VERSION 5.8 ;
BUSBITCHARS "[]" ;
DIVIDERCHAR "/" ;
UNITS
  DATABASE MICRONS 1000 ;
END UNITS
MANUFACTURINGGRID 0.005 ;
PROPERTYDEFINITIONS
  LAYER LEF58_CUTCLASS STRING ;
  LAYER LEF58_MINIMUMCUT STRING ;
END PROPERTYDEFINITIONS
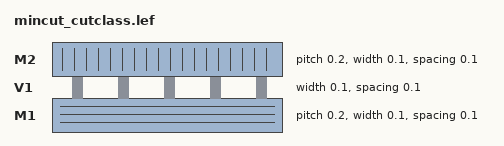
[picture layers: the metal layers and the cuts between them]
LAYER M1
  TYPE ROUTING ;
  DIRECTION HORIZONTAL ;
  PITCH 0.2 ;
  WIDTH 0.1 ;
  SPACING 0.1 ;
  PROPERTY LEF58_MINIMUMCUT "MINIMUMCUT 2 WIDTH 0.5 ;" ;
END M1
LAYER V1
  TYPE CUT ;
  SPACING 0.1 ;
  WIDTH 0.1 ;
  PROPERTY LEF58_CUTCLASS "CUTCLASS VA WIDTH 0.1 ; CUTCLASS VB WIDTH 0.1 LENGTH 0.2 ;" ;
END V1
LAYER M2
  TYPE ROUTING ;
  DIRECTION VERTICAL ;
  PITCH 0.2 ;
  WIDTH 0.1 ;
  SPACING 0.1 ;
  PROPERTY LEF58_MINIMUMCUT "MINIMUMCUT CUTCLASS VA 2 CUTCLASS VB 1 WIDTH 0.5 ;" ;
END M2
END LIBRARY
